VERSION 5.7 ;
  NOWIREEXTENSIONATPIN ON ;
  DIVIDERCHAR "/" ;
  BUSBITCHARS "[]" ;
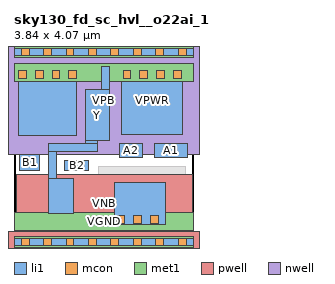
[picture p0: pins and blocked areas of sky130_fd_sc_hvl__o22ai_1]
MACRO sky130_fd_sc_hvl__o22ai_1
  CLASS BLOCK ;
  FOREIGN sky130_fd_sc_hvl__o22ai_1 ;
  ORIGIN 0.000 0.000 ;
  SIZE 3.840 BY 4.070 ;
  PIN A1
    ANTENNAGATEAREA 1.125000 ;
    PORT
      LAYER li1 ;
        RECT 3.005 1.805 3.715 2.120 ;
    END
  END A1
  PIN A2
    ANTENNAGATEAREA 1.125000 ;
    PORT
      LAYER li1 ;
        RECT 2.250 1.805 2.755 2.120 ;
    END
  END A2
  PIN B1
    ANTENNAGATEAREA 1.125000 ;
    PORT
      LAYER li1 ;
        RECT 0.125 1.535 0.550 1.865 ;
    END
  END B1
  PIN B2
    ANTENNAGATEAREA 1.125000 ;
    PORT
      LAYER li1 ;
        RECT 1.085 1.535 1.595 1.750 ;
    END
  END B2
  PIN VGND
    USE GROUND ;
    PORT
      LAYER li1 ;
        RECT 2.150 0.365 3.250 1.275 ;
      LAYER mcon ;
        RECT 2.200 0.395 2.370 0.565 ;
        RECT 2.560 0.395 2.730 0.565 ;
        RECT 2.920 0.395 3.090 0.565 ;
      LAYER met1 ;
        RECT 0.000 0.255 3.840 0.625 ;
    END
  END VGND
  PIN VNB
    ANTENNADIFFAREA 0.652800 ;
    PORT
      LAYER pwell ;
        RECT 0.050 0.215 3.820 1.445 ;
        RECT -0.130 -0.215 3.970 0.215 ;
      LAYER li1 ;
        RECT 0.000 -0.085 3.840 0.085 ;
      LAYER mcon ;
        RECT 0.155 -0.085 0.325 0.085 ;
        RECT 0.635 -0.085 0.805 0.085 ;
        RECT 1.115 -0.085 1.285 0.085 ;
        RECT 1.595 -0.085 1.765 0.085 ;
        RECT 2.075 -0.085 2.245 0.085 ;
        RECT 2.555 -0.085 2.725 0.085 ;
        RECT 3.035 -0.085 3.205 0.085 ;
        RECT 3.515 -0.085 3.685 0.085 ;
      LAYER met1 ;
        RECT 0.000 -0.115 3.840 0.115 ;
    END
  END VNB
  PIN VPB
    ANTENNADIFFAREA 0.652800 ;
    PORT
      LAYER nwell ;
        RECT -0.330 1.885 4.170 4.485 ;
      LAYER li1 ;
        RECT 0.000 3.985 3.840 4.155 ;
      LAYER mcon ;
        RECT 0.155 3.985 0.325 4.155 ;
        RECT 0.635 3.985 0.805 4.155 ;
        RECT 1.115 3.985 1.285 4.155 ;
        RECT 1.595 3.985 1.765 4.155 ;
        RECT 2.075 3.985 2.245 4.155 ;
        RECT 2.555 3.985 2.725 4.155 ;
        RECT 3.035 3.985 3.205 4.155 ;
        RECT 3.515 3.985 3.685 4.155 ;
      LAYER met1 ;
        RECT 0.000 3.955 3.840 4.185 ;
    END
  END VPB
  PIN VPWR
    USE POWER ;
    PORT
      LAYER li1 ;
        RECT 0.090 2.280 1.345 3.755 ;
        RECT 2.305 2.300 3.615 3.755 ;
      LAYER mcon ;
        RECT 0.095 3.505 0.265 3.675 ;
        RECT 0.455 3.505 0.625 3.675 ;
        RECT 0.815 3.505 0.985 3.675 ;
        RECT 1.175 3.505 1.345 3.675 ;
        RECT 2.335 3.505 2.505 3.675 ;
        RECT 2.695 3.505 2.865 3.675 ;
        RECT 3.055 3.505 3.225 3.675 ;
        RECT 3.415 3.505 3.585 3.675 ;
      LAYER met1 ;
        RECT 0.000 3.445 3.840 3.815 ;
    END
  END VPWR
  PIN Y
    ANTENNADIFFAREA 0.742500 ;
    PORT
      LAYER li1 ;
        RECT 1.875 3.260 2.045 3.755 ;
        RECT 1.525 2.175 2.045 3.260 ;
        RECT 1.525 2.100 1.795 2.175 ;
        RECT 0.735 1.930 1.795 2.100 ;
        RECT 0.735 1.355 0.905 1.930 ;
        RECT 0.735 0.615 1.270 1.355 ;
    END
  END Y
  OBS
      LAYER li1 ;
        RECT 1.800 1.455 3.670 1.625 ;
        RECT 0.160 0.435 0.490 1.355 ;
        RECT 1.800 0.435 1.970 1.455 ;
        RECT 3.420 0.525 3.670 1.455 ;
        RECT 0.160 0.265 1.970 0.435 ;
  END
END sky130_fd_sc_hvl__o22ai_1
END LIBRARY

